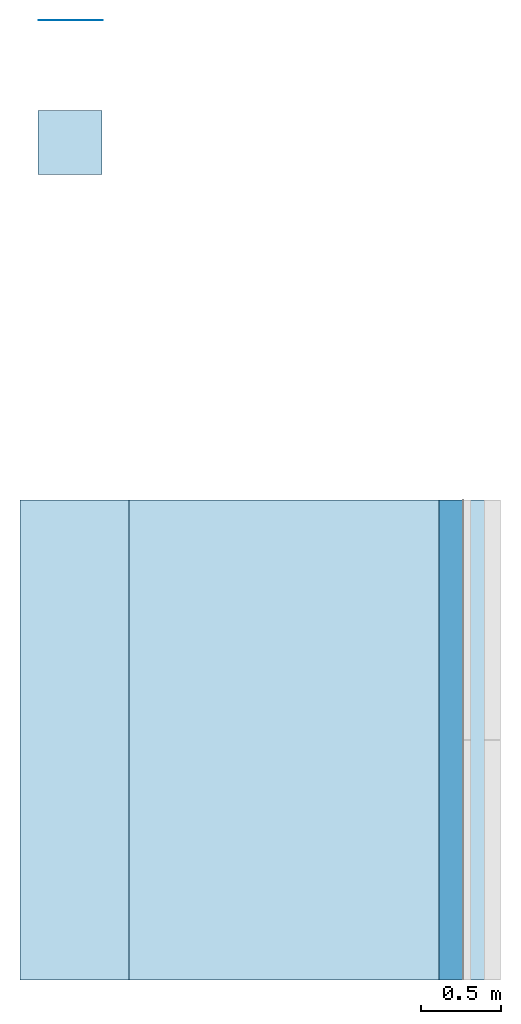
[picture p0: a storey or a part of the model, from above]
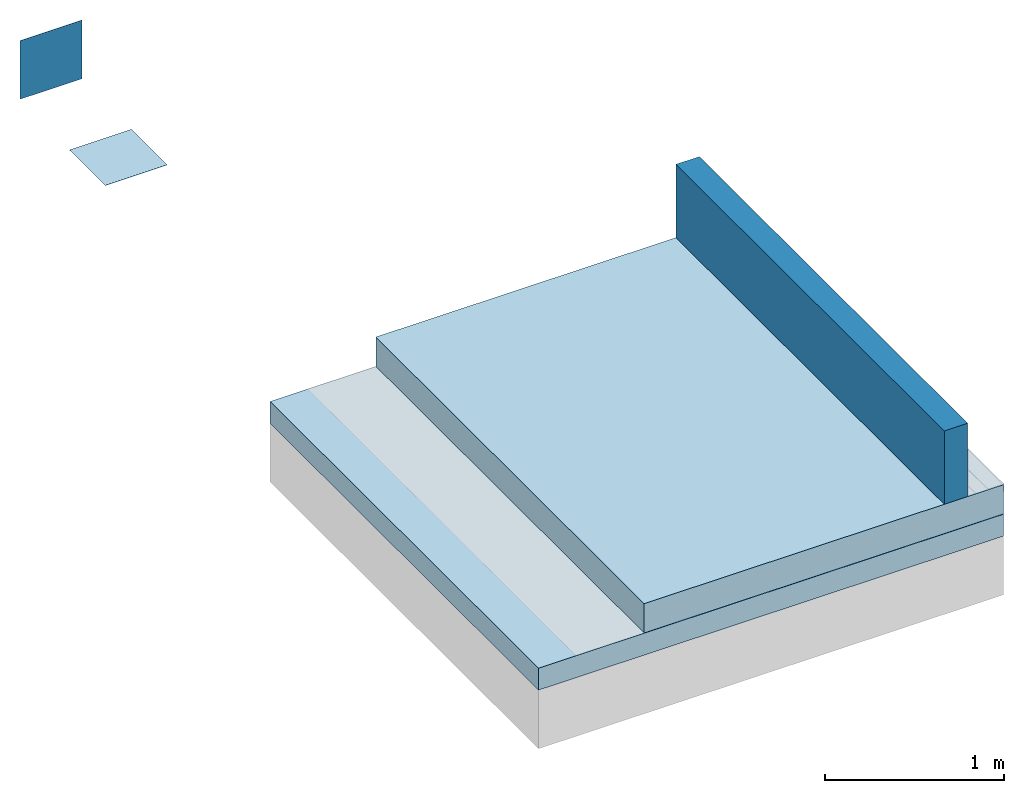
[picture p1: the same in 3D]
Properties of the parts of a building model (IFC2X3)

# File
Description: ViewDefinition [CoordinationView_V2.0], RevitIdentifiers [VersionGUID: 8294a368-1006-45e9-a886-03405451c49e, NumberOfSaves: 9], CoordinateReference [CoordinateBase: Coordenadas compartilhadas]
File name: 0001
Time: 2024-04-25T08:08:25
Written by: ODA IFC SDK 22.8
Made in: 22.1.50.17 - Exporter 22.6.2.0 - IU alternativa 22.6.2.0

# IfcProject, 0001
LongName: Laje de Subpressão - Amphibia; Phase: Status do projeto

# IfcSite, Default
RefLatitude: 42, 21, 31, 181944; RefLongitude: -71, -3, -24, -263304; RefElevation: 0 m

# IfcBuilding
Pset_BuildingCommon - NumberOfStoreys: 1; IsLandmarked: no

# IfcBuildingStorey: Nível:Cabeça de 8 mm, ARQ Térreo
LongName: ARQ Térreo; Elevation: -0.0025238 m

# IfcBuildingElementProxy: AMPHIBIA:AMPHIBIA, AMPHIBIA:AMPHIBIA:301965
In: ARQ Térreo
Type - Material: #solo, #Amphibia
Pset_BuildingElementProxyCommon - Reference: AMPHIBIA; sets with these values: 2
Pset_ProvisionForVoid - Width: 3 m; Height: 3 m; Depth: 3 m

# IfcBuildingElementProxy: Amphibia Pressure Corner 270°1:Amphibia Pressure Corner 270°, Amphibia Pressure Corner 270°1:Amphibia Pressure Corner 270°:305428
In: ARQ Térreo
Type - Material: Alumín. 1
Pset_BuildingElementProxyCommon - Reference: Amphibia Pressure Corner 270°; sets with these values: 2

# IfcBuildingElementProxy: Amphibia Pressure Corner 270°:Amphibia Pressure Corner 270°, Amphibia Pressure Corner 270°:Amphibia Pressure Corner 270°:305217
In: ARQ Térreo
Type - Material: Alumín. 1
Pset_BuildingElementProxyCommon - Reference: Amphibia Pressure Corner 270°; sets with these values: 2

# IfcBuildingElementProxy: Amphibia Pressure Corner 90°1:Amphibia Pressure Corner 90°, Amphibia Pressure Corner 90°1:Amphibia Pressure Corner 90°:304764
In: ARQ Térreo
Type - Material: Alumín. 1
Pset_BuildingElementProxyCommon - Reference: Amphibia Pressure Corner 90°; sets with these values: 2

# IfcBuildingElementProxy: Amphibia Pressure Corner 90°:Amphibia Pressure Corner 90°, Amphibia Pressure Corner 90°:Amphibia Pressure Corner 90°:304475
In: ARQ Térreo
Type - Material: Alumín. 1
Pset_BuildingElementProxyCommon - Reference: Amphibia Pressure Corner 90°; sets with these values: 2

# IfcBuildingElementProxy: Amphibia Pressure Line1:Amphibia Pressure Line, Amphibia Pressure Line1:Amphibia Pressure Line:305790
In: ARQ Térreo
Type - Material: Alumín. 1
Pset_BuildingElementProxyCommon - Reference: Amphibia Pressure Line; sets with these values: 2
Pset_ProvisionForVoid - Width: 1.5 m; Height: 0.001 m; Depth: 0.001 m

# IfcBuildingElementProxy: Amphibia Pressure Line:Amphibia Pressure Line, Amphibia Pressure Line:Amphibia Pressure Line:305598
In: ARQ Térreo
Type - Material: Alumín. 1
Pset_BuildingElementProxyCommon - Reference: Amphibia Pressure Line; sets with these values: 2
Pset_ProvisionForVoid - Width: 1.5 m; Height: 0.001 m; Depth: 0.001 m

# IfcSlab: Piso:IMPH_AMPHIBIA, Piso:IMPH_AMPHIBIA:293954
In: ARQ Térreo
Type - PredefinedType: FLOOR; Material: #Amphibia 0.0013 m
Type - Pset_SlabCommon - IsExternal: no
Pset_QuantityTakeOff - Reference: IMPH_AMPHIBIA; sets with these values: 2
Pset_SlabCommon - LoadBearing: no; PitchAngle: 0 deg; Reference: IMPH_AMPHIBIA

# IfcSlab: Piso:LAJE DE SUBPRESSÃO, Piso:LAJE DE SUBPRESSÃO:297711
In: ARQ Térreo
Type - PredefinedType: FLOOR; Material: #concreto magro 0.15 m
Type - Pset_SlabCommon - IsExternal: no
Pset_QuantityTakeOff - Reference: LAJE DE SUBPRESSÃO; sets with these values: 2
Pset_SlabCommon - LoadBearing: no; PitchAngle: 0 deg; Reference: LAJE DE SUBPRESSÃO

# IfcSlab: Piso:Piso:LAJE CONCRETO, Piso:Piso:LAJE CONCRETO:293935
In: ARQ Térreo
Type - PredefinedType: FLOOR; Material: #concreto 0.2 m
Type - Pset_SlabCommon - IsExternal: no
Pset_QuantityTakeOff - Reference: Piso:LAJE CONCRETO; sets with these values: 2
Pset_SlabCommon - Reference: Piso:LAJE CONCRETO; LoadBearing: no; PitchAngle: 0 deg

# IfcWallStandardCase: Parede básica:IMPV_AMPHIBIA, Parede básica:IMPV_VP1000:459587
In: ARQ Térreo
Type - PredefinedType: STANDARD; Material: #Amphibia 0.0013 m
Type - Pset_WallCommon - IsExternal: yes; ThermalTransmittance: 16.4516 kg/K/s3
Pset_QuantityTakeOff - Reference: IMPV_VP1000; sets with these values: 2
Pset_WallCommon - LoadBearing: no; ExtendToStructure: no; Reference: IMPV_VP1000

# IfcWallStandardCase: Parede básica:Parede básica:Parede Concreto, Parede básica:Parede Concreto:395312
In: ARQ Térreo
Type - PredefinedType: STANDARD; Material: #concreto 0.15 m
Type - Pset_WallCommon - IsExternal: yes; ThermalTransmittance: 6.97333 kg/K/s3
Pset_QuantityTakeOff - Reference: Parede Concreto; sets with these values: 2
Pset_WallCommon - LoadBearing: no; Reference: Parede Concreto; ExtendToStructure: no
